VERSION 5.8 ;
BUSBITCHARS "[]" ;
DIVIDERCHAR "/" ;

UNITS
  DATABASE MICRONS 2000 ;
END UNITS

MANUFACTURINGGRID 0.0005 ;

PROPERTYDEFINITIONS
  LAYER LEF58_SPACING STRING ;
END PROPERTYDEFINITIONS

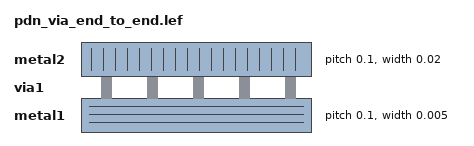
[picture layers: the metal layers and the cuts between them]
LAYER metal1
  TYPE ROUTING ;
  DIRECTION HORIZONTAL ;
  PITCH 0.1 ;
  WIDTH 0.005 ;
END metal1

LAYER via1
  TYPE CUT ;
END via1

# Line ends narrower than 0.03 (60 DBU) need 0.05 (100 DBU) beyond them and
# 0.01 (20 DBU) to either side; two facing line ends need only 0.03 (60 DBU)
# and must overlap.
LAYER metal2
  TYPE ROUTING ;
  DIRECTION VERTICAL ;
  PITCH 0.1 ;
  WIDTH 0.02 ;
  PROPERTY LEF58_SPACING
    "SPACING 0.05 ENDOFLINE 0.03 WITHIN 0.01 ENDTOEND 0.03 ;" ;
END metal2

# metal2 landings, 0.02 (narrow, a line end) and 0.05 (wide) across.  The
# metal1 and via1 boxes are tiny and the cell has neither layer.
VIA narrow_via DEFAULT
  LAYER metal1 ;
    RECT -0.0025 -0.0025 0.0025 0.0025 ;
  LAYER via1 ;
    RECT -0.0025 -0.0025 0.0025 0.0025 ;
  LAYER metal2 ;
    RECT -0.01 -0.02 0.01 0.02 ;
END narrow_via

VIA wide_via DEFAULT
  LAYER metal1 ;
    RECT -0.0025 -0.0025 0.0025 0.0025 ;
  LAYER via1 ;
    RECT -0.0025 -0.0025 0.0025 0.0025 ;
  LAYER metal2 ;
    RECT -0.025 -0.02 0.025 0.02 ;
END wide_via

SITE EOL_SITE
  CLASS CORE ;
  SIZE 0.1 BY 0.1 ;
END EOL_SITE

# One narrow metal2 line at (80 100) (120 190) DBU from the cell origin, its
# top edge a line end.
MACRO EOL_CELL
  CLASS CORE ;
  SIZE 0.1 BY 0.1 ;
  SITE EOL_SITE ;
  OBS
    LAYER metal2 ;
      RECT 0.04 0.05 0.06 0.095 ;
  END
END EOL_CELL

END LIBRARY
